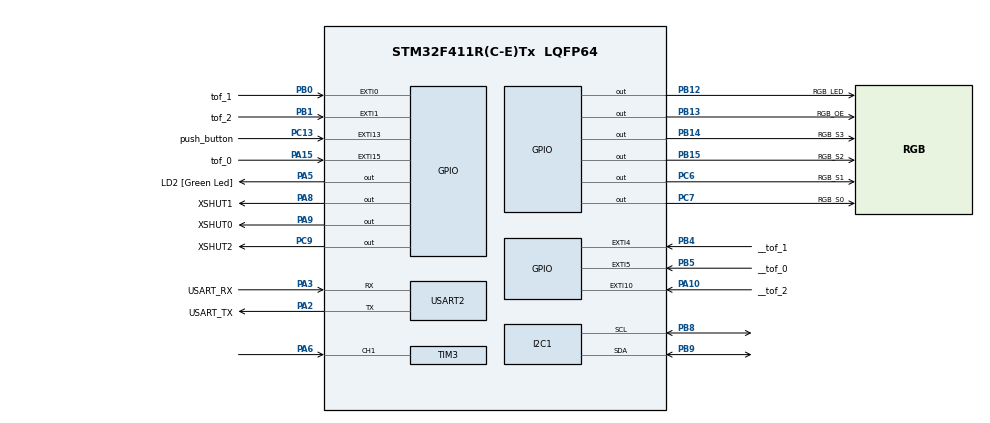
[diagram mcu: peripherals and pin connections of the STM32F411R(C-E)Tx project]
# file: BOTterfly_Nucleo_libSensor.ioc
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I2C1.I2C_Mode=I2C_Fast
Mcu.Family=STM32F4
Mcu.Name=STM32F411R(C-E)Tx
Mcu.Package=LQFP64
NVIC.EXTI0_IRQn=true\:0\:0\:false\:false\:true\:true\:true
NVIC.EXTI15_10_IRQn=true\:0\:0\:false\:false\:true\:true\:true
NVIC.EXTI1_IRQn=true\:0\:0\:false\:false\:true\:true\:true
NVIC.PriorityGroup=NVIC_PRIORITYGROUP_0
NVIC.TIM3_IRQn=true\:0\:0\:false\:false\:true\:true\:true
NVIC.USART2_IRQn=true\:0\:0\:false\:false\:true\:true\:true
PA10.GPIO_Label=__tof_2
PA10.Signal=GPXTI10
PA13.GPIO_Label=TMS
PA13.Mode=Serial_Wire
PA13.Signal=SYS_JTMS-SWDIO
PA14.GPIO_Label=TCK
PA14.Mode=Serial_Wire
PA14.Signal=SYS_JTCK-SWCLK
PA15.GPIO_Label=tof_0
PA15.Signal=GPXTI15
PA2.GPIO_Label=USART_TX
PA2.Mode=Asynchronous
PA2.Signal=USART2_TX
PA3.GPIO_Label=USART_RX
PA3.Mode=Asynchronous
PA3.Signal=USART2_RX
PA5.GPIO_Label=LD2 [Green Led]
PA5.Signal=GPIO_Output
PA6.Signal=S_TIM3_CH1
PA8.GPIO_Label=XSHUT1
PA8.Signal=GPIO_Output
PA9.GPIO_Label=XSHUT0
PA9.Signal=GPIO_Output
PB0.GPIO_Label=tof_1
PB0.Signal=GPXTI0
PB1.GPIO_Label=tof_2
PB1.Signal=GPXTI1
PB12.GPIO_Label=RGB_LED
PB12.Signal=GPIO_Output
PB13.GPIO_Label=RGB_OE
PB13.Signal=GPIO_Output
PB14.GPIO_Label=RGB_S3
PB14.Signal=GPIO_Output
PB15.GPIO_Label=RGB_S2
PB15.Signal=GPIO_Output
PB3.GPIO_Label=SWO
PB3.Signal=SYS_JTDO-SWO
PB4.GPIO_Label=__tof_1
PB4.Signal=GPXTI4
PB5.GPIO_Label=__tof_0
PB5.Signal=GPXTI5
PB8.Mode=I2C
PB8.Signal=I2C1_SCL
PB9.Mode=I2C
PB9.Signal=I2C1_SDA
PC13-ANTI_TAMP.GPIO_Label=push_button
PC13-ANTI_TAMP.Signal=GPXTI13
PC14-OSC32_IN.Mode=LSE-External-Oscillator
PC14-OSC32_IN.Signal=RCC_OSC32_IN
PC15-OSC32_OUT.Mode=LSE-External-Oscillator
PC15-OSC32_OUT.Signal=RCC_OSC32_OUT
PC6.GPIO_Label=RGB_S1
PC6.Signal=GPIO_Output
PC7.GPIO_Label=RGB_S0
PC7.Signal=GPIO_Output
PC9.GPIO_Label=XSHUT2
PC9.Signal=GPIO_Output
PH0\ -\ OSC_IN.Mode=HSE-External-Clock-Source
PH0\ -\ OSC_IN.Signal=RCC_OSC_IN
PH1\ -\ OSC_OUT.Mode=HSE-External-Clock-Source
PH1\ -\ OSC_OUT.Signal=RCC_OSC_OUT
ProjectManager.HeapSize=0x200
ProjectManager.StackSize=0x400
ProjectManager.TargetToolchain=STM32CubeIDE
RCC.48MHZClocksFreq_Value=84000000
RCC.AHBFreq_Value=84000000
RCC.APB1CLKDivider=RCC_HCLK_DIV2
RCC.APB1Freq_Value=42000000
RCC.APB1TimFreq_Value=84000000
RCC.APB2Freq_Value=84000000
RCC.APB2TimFreq_Value=84000000
RCC.CortexFreq_Value=84000000
RCC.FLatency-AdvancedSettings=FLASH_LATENCY_2
RCC.HCLKFreq_Value=84000000
RCC.HSE_VALUE=8000000
RCC.HSI_VALUE=16000000
RCC.PLLN=336
RCC.PLLP=RCC_PLLP_DIV4
RCC.SYSCLKFreq_VALUE=84000000
RCC.SYSCLKSource=RCC_SYSCLKSOURCE_PLLCLK
RCC.VCOOutputFreq_Value=336000000
SH.S_TIM3_CH1.0=TIM3_CH1,Input_Capture1_from_TI1
TIM3.Channel-Input_Capture1_from_TI1=TIM_CHANNEL_1
TIM3.Prescaler=42-1
USART2.VirtualMode=VM_ASYNC
board=NUCLEO-F411RE

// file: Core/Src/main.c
/* USER CODE BEGIN Header */
/**
 ******************************************************************************
 * @file           : main.c
 * @brief          : Main program body
 ******************************************************************************
 * @attention
 *
 * <h2><center>&copy; Copyright (c) 2021 STMicroelectronics.
 * All rights reserved.</center></h2>
 *
 * This software component is licensed by ST under BSD 3-Clause license,
 * the "License"; You may not use this file except in compliance with the
 * License. You may obtain a copy of the License at:
 *                        opensource.org/licenses/BSD-3-Clause
 *
 ******************************************************************************
 */
/* USER CODE END Header */
#include "main.h"
#include "i2c.h"
#include "tim.h"
#include "usart.h"
#include "gpio.h"

/* USER CODE BEGIN Includes */
#include "BOTterfly-H/config.h"
/* USER CODE END Includes */

/* USER CODE BEGIN PD */
//#define nbOfSensors 1
/* USER CODE END PD */

/* USER CODE BEGIN PV */
//VL53L0X_Dev_t myDevice[nbOfSensors];

char msg[1];
int it_uart = 0;
/* USER CODE END PV */

void SystemClock_Config(void);

int main(void)
{

	/* MCU Configuration--------------------------------------------------------*/

	/* Reset of all peripherals, Initializes the Flash interface and the Systick. */
	HAL_Init();

	/* Configure the system clock */
	SystemClock_Config();

	/* Initialize all configured peripherals */
	MX_GPIO_Init();
	MX_USART2_UART_Init();
	MX_I2C1_Init();
	MX_TIM3_Init();
	/* USER CODE BEGIN 2 */
	// Liaison série
	HAL_UART_Receive_IT(&huart2,(uint8_t*)msg,1);

	printf("\r\n --------------------- TIME OF FLIGHT --------------------- \r\n");

	TOF_Init_SetI2C(&TOF_Sensor[0], &hi2c1, 0x55);
	TOF_Init_SetGPIOs(&TOF_Sensor[0], XSHUT0_GPIO_Port, XSHUT0_Pin, tof_0_GPIO_Port, tof_0_Pin);
	TOF_Init_SetEXTI(&TOF_Sensor[0], tof_0_EXTI_IRQn);

	TOF_Init_SetI2C(&TOF_Sensor[1], &hi2c1, 0x58);
	TOF_Init_SetGPIOs(&TOF_Sensor[1], XSHUT1_GPIO_Port, XSHUT1_Pin, tof_1_GPIO_Port, tof_1_Pin);
	TOF_Init_SetEXTI(&TOF_Sensor[1], tof_1_EXTI_IRQn);

	TOF_Init_SetI2C(&TOF_Sensor[2], &hi2c1, 0x5b);
	TOF_Init_SetGPIOs(&TOF_Sensor[2], XSHUT2_GPIO_Port, XSHUT2_Pin, tof_2_GPIO_Port, tof_2_Pin);
	TOF_Init_SetEXTI(&TOF_Sensor[2], tof_2_EXTI_IRQn);

	TOF_Init(TOF_Sensor);

	printf("\r\n ---------------------   RGB SENSOR   --------------------- \r\n");

	RGB_Init_SetTimer(&RGB_Sensor, &htim3, TIM_CHANNEL_1);

	RGB_Init_SetParamGPIOs(&RGB_Sensor, RGB_OE_GPIO_Port, RGB_OE_Pin, RGB_LED_GPIO_Port, RGB_LED_Pin);
	RGB_Init_SetOutFreqGPIOs(&RGB_Sensor, RGB_S0_GPIO_Port, RGB_S0_Pin, RGB_S1_GPIO_Port, RGB_S1_Pin);
	RGB_Init_SetColorFilterGPIOs(&RGB_Sensor, RGB_S2_GPIO_Port, RGB_S2_Pin, RGB_S3_GPIO_Port, RGB_S3_Pin);

	RGB_Init(&RGB_Sensor);

	/* USER CODE END 2 */

	/* Infinite loop */
	/* USER CODE BEGIN WHILE */
	while (1)
	{
		if(it_uart){
			if(msg[0] == '\r'){
				printf("\r\n");
			}else{
				HAL_UART_Transmit(&huart2, (uint8_t*)msg, 1, HAL_MAX_DELAY);
			}
			it_uart = 0;
		}

		printf("\r\n ----------------------- RGB SENSOR ----------------------- \r\n");
		if(RGB_Sensor.isFloorRed){
			printf("The floor is red\r\n");
		}else{
			printf("The floor is not red\r\n");
		}
		printf("RED : %d\r\n", RGB_Sensor.red);
		printf("GREEN : %d\r\n", RGB_Sensor.green);
		printf("BLUE : %d\r\n", RGB_Sensor.blue);

		printf("\r\n ----------------------- TOF SENSORS ----------------------- \r\n");
		printf("Tof 0 - DISTANCE = %d mm\r\n",TOF_Sensor[0].rangeMillimeter);
		printf("Tof 1 - DISTANCE = %d mm\r\n",TOF_Sensor[1].rangeMillimeter);
		printf("Tof 2 - DISTANCE = %d mm\r\n",TOF_Sensor[2].rangeMillimeter);

		HAL_Delay(250);

		/* USER CODE END WHILE */

	}
}

void SystemClock_Config(void)
{
	RCC_OscInitTypeDef RCC_OscInitStruct = {0};
	RCC_ClkInitTypeDef RCC_ClkInitStruct = {0};

	/** Configure the main internal regulator output voltage
	 */
	__HAL_RCC_PWR_CLK_ENABLE();
	__HAL_PWR_VOLTAGESCALING_CONFIG(PWR_REGULATOR_VOLTAGE_SCALE1);
	/** Initializes the RCC Oscillators according to the specified parameters
	 * in the RCC_OscInitTypeDef structure.
	 */
	RCC_OscInitStruct.OscillatorType = RCC_OSCILLATORTYPE_HSI;
	RCC_OscInitStruct.HSIState = RCC_HSI_ON;
	RCC_OscInitStruct.HSICalibrationValue = RCC_HSICALIBRATION_DEFAULT;
	RCC_OscInitStruct.PLL.PLLState = RCC_PLL_ON;
	RCC_OscInitStruct.PLL.PLLSource = RCC_PLLSOURCE_HSI;
	RCC_OscInitStruct.PLL.PLLM = 8;
	RCC_OscInitStruct.PLL.PLLN = 80;
	RCC_OscInitStruct.PLL.PLLP = RCC_PLLP_DIV2;
	RCC_OscInitStruct.PLL.PLLQ = 4;
	if (HAL_RCC_OscConfig(&RCC_OscInitStruct) != HAL_OK)
	{
		Error_Handler();
	}
	/** Initializes the CPU, AHB and APB buses clocks
	 */
	RCC_ClkInitStruct.ClockType = RCC_CLOCKTYPE_HCLK|RCC_CLOCKTYPE_SYSCLK
			|RCC_CLOCKTYPE_PCLK1|RCC_CLOCKTYPE_PCLK2;
	RCC_ClkInitStruct.SYSCLKSource = RCC_SYSCLKSOURCE_PLLCLK;
	RCC_ClkInitStruct.AHBCLKDivider = RCC_SYSCLK_DIV1;
	RCC_ClkInitStruct.APB1CLKDivider = RCC_HCLK_DIV2;
	RCC_ClkInitStruct.APB2CLKDivider = RCC_HCLK_DIV1;

	if (HAL_RCC_ClockConfig(&RCC_ClkInitStruct, FLASH_LATENCY_2) != HAL_OK)
	{
		Error_Handler();
	}
}

/* USER CODE BEGIN 4 */
void HAL_UART_RxCpltCallback(UART_HandleTypeDef *huart)
{
	HAL_UART_Receive_IT(&huart2,(uint8_t*)msg,1);
	if(huart->Instance == USART2){
		it_uart = 1;
	}
}

/* USER CODE END 4 */

void Error_Handler(void)
{
	__disable_irq();
	while (1)
	{
	}
}

/************************ (C) COPYRIGHT STMicroelectronics *****END OF FILE****/
